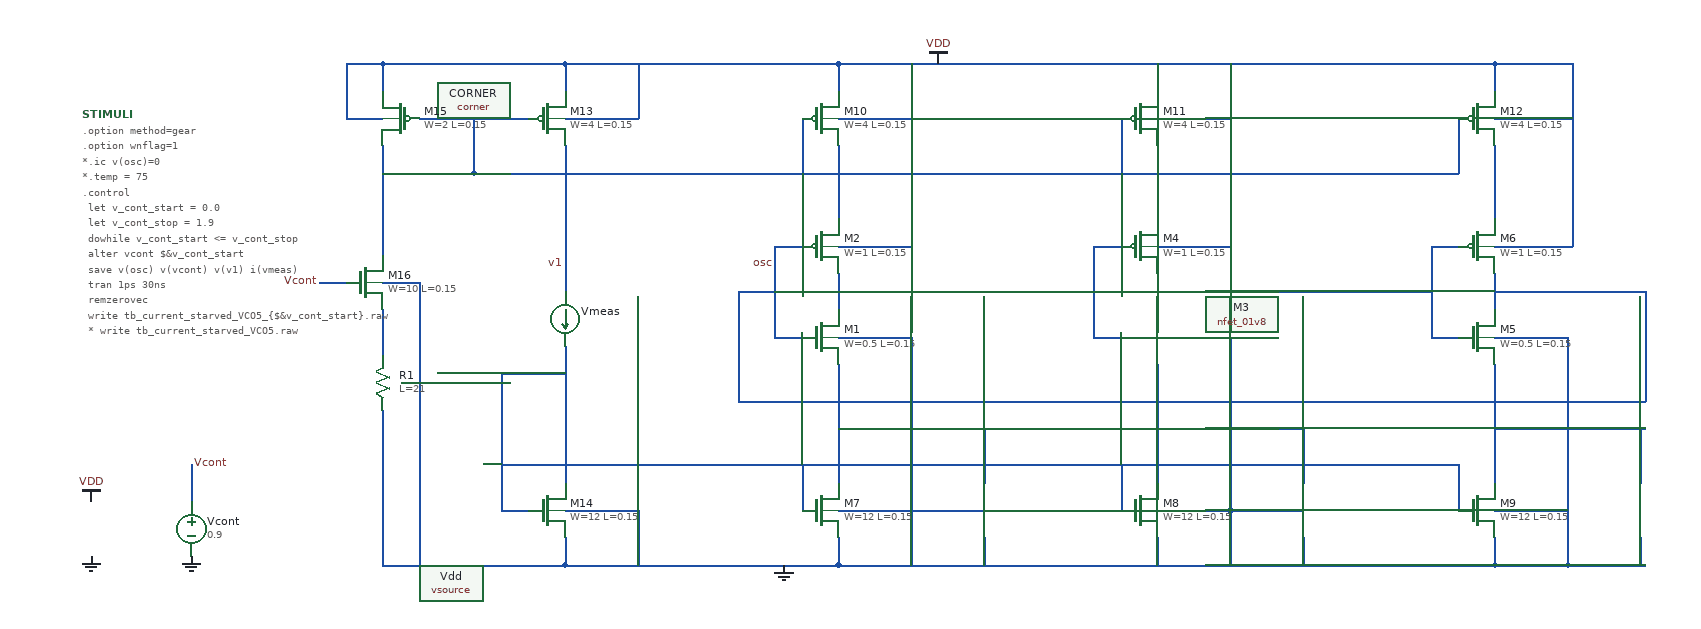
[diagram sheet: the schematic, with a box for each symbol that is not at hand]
v {xschem version=3.4.5 file_version=1.2
}
G {}
K {}
V {}
S {}
E {}
B 2 40 -1430 1140 -730 {flags=graph
y1=1.7
y2=1.8
ypos1=0
ypos2=2
divy=5
subdivy=1
unity=1
x1=0
x2=3e-08
divx=5
subdivx=1
xlabmag=1.0
ylabmag=1.0
node=osc
color=6
dataset=-1
unitx=1
logx=0
logy=0
}
N 880 -410 880 -370 {
lab=#net1}
N 810 -440 840 -440 {
lab=osc}
N 810 -440 810 -340 {
lab=osc}
N 810 -340 840 -340 {
lab=osc}
N 1230 -410 1230 -370 {
lab=#net2}
N 1160 -440 1190 -440 {
lab=#net1}
N 1160 -440 1160 -340 {
lab=#net1}
N 1160 -340 1190 -340 {
lab=#net1}
N 880 -390 1160 -390 {
lab=#net1}
N 1600 -410 1600 -370 {
lab=osc}
N 1530 -440 1560 -440 {
lab=#net2}
N 1530 -440 1530 -340 {
lab=#net2}
N 1530 -340 1560 -340 {
lab=#net2}
N 1230 -390 1530 -390 {
lab=#net2}
N 880 -120 880 -90 {
lab=GND}
N 880 -90 1600 -90 {
lab=GND}
N 1600 -120 1600 -90 {
lab=GND}
N 1230 -120 1230 -90 {
lab=GND}
N 1600 -390 1765 -390 {
lab=osc}
N 1765 -390 1765 -270 {
lab=osc}
N 770 -270 1765 -270 {
lab=osc}
N 770 -390 770 -270 {
lab=osc}
N 770 -390 810 -390 {
lab=osc}
N 880 -550 880 -470 {
lab=#net3}
N 880 -550 880 -470 {
lab=#net3}
N 1230 -550 1230 -470 {
lab=#net4}
N 1600 -550 1600 -470 {
lab=#net5}
N 880 -640 880 -610 {
lab=VDD}
N 880 -640 1600 -640 {
lab=VDD}
N 1600 -640 1600 -610 {
lab=VDD}
N 1230 -640 1230 -610 {
lab=VDD}
N 580 -640 580 -610 {
lab=VDD}
N 580 -640 880 -640 {
lab=VDD}
N 580 -120 580 -90 {
lab=GND}
N 580 -90 880 -90 {
lab=GND}
N 1600 -310 1600 -180 {
lab=#net6}
N 1230 -310 1230 -180 {
lab=#net7}
N 880 -310 880 -180 {
lab=#net8}
N 880 -440 960 -440 {
lab=VDD}
N 960 -640 960 -440 {
lab=VDD}
N 880 -340 960 -340 {
lab=GND}
N 960 -340 960 -90 {
lab=GND}
N 880 -150 960 -150 {
lab=GND}
N 1230 -340 1310 -340 {
lab=GND}
N 1310 -340 1310 -90 {
lab=GND}
N 1230 -150 1310 -150 {
lab=GND}
N 1600 -340 1680 -340 {
lab=GND}
N 1680 -340 1680 -90 {
lab=GND}
N 1600 -90 1680 -90 {
lab=GND}
N 880 -580 960 -580 {
lab=VDD}
N 1230 -580 1310 -580 {
lab=VDD}
N 1230 -440 1310 -440 {
lab=VDD}
N 1310 -640 1310 -440 {
lab=VDD}
N 1600 -580 1685 -580 {
lab=VDD}
N 1600 -640 1685 -640 {
lab=VDD}
N 1685 -640 1685 -440 {
lab=VDD}
N 1600 -440 1685 -440 {
lab=VDD}
N 1560 -580 1560 -520 {
lab=#net9}
N 1190 -580 1190 -520 {
lab=#net9}
N 510 -200 1560 -200 {
lab=#net10}
N 1560 -200 1560 -150 {
lab=#net10}
N 1190 -200 1190 -150 {
lab=#net10}
N 840 -200 840 -150 {
lab=#net10}
N 580 -580 660 -580 {
lab=VDD}
N 660 -640 660 -580 {
lab=VDD}
N 580 -640 660 -640 {
lab=VDD}
N 580 -150 660 -150 {
lab=GND}
N 660 -150 660 -90 {
lab=GND}
N 170 -200 170 -160 {
lab=Vcont}
N 580 -330 580 -180 {
lab=#net10}
N 580 -550 580 -390 {
lab=v1}
N 510 -300 580 -300 {
lab=#net10}
N 840 -580 840 -520 {
lab=#net9}
N 380 -640 380 -610 {
lab=VDD}
N 340 -580 380 -580 {
lab=VDD}
N 340 -640 340 -580 {
lab=VDD}
N 340 -640 380 -640 {
lab=VDD}
N 310 -400 340 -400 {
lab=Vcont}
N 380 -550 380 -430 {
lab=#net9}
N 420 -640 580 -640 {
lab=VDD}
N 380 -370 380 -320 {
lab=#net11}
N 380 -90 580 -90 {
lab=GND}
N 420 -190 420 -90 {
lab=GND}
N 420 -400 420 -190 {
lab=GND}
N 380 -400 420 -400 {
lab=GND}
N 380 -260 380 -90 {
lab=GND}
N 510 -150 540 -150 {
lab=#net10}
N 510 -300 510 -150 {
lab=#net10}
N 400 -290 420 -290 {
lab=GND}
N 480 -580 480 -520 {
lab=#net9}
N 960 -150 1040 -150 {
lab=GND}
N 880 -240 1040 -240 {
lab=#net8}
N 1310 -150 1390 -150 {
lab=GND}
N 1230 -240 1390 -240 {
lab=#net7}
N 1600 -240 1765 -240 {
lab=#net6}
N 1680 -90 1765 -90 {
lab=GND}
N 1040 -120 1040 -90 {
lab=GND}
N 1040 -240 1040 -180 {
lab=#net8}
N 1310 -150 1390 -150 {
lab=GND}
N 1390 -120 1390 -90 {
lab=GND}
N 1390 -240 1390 -180 {
lab=#net7}
N 1760 -120 1760 -90 {
lab=GND}
N 1760 -240 1760 -180 {
lab=#net6}
N 1600 -150 1680 -150 {
lab=GND}
N 380 -640 420 -640 {
lab=VDD}
N 420 -580 540 -580 {
lab=#net9}
N 480 -520 1560 -520 {
lab=#net9}
N 380 -520 480 -520 {
lab=#net9}
C {devices/vdd.sym} 990 -640 0 0 {name=l1 lab=VDD}
C {devices/gnd.sym} 820 -90 0 0 {name=l2 lab=GND}
C {sky130_fd_pr/nfet_01v8.sym} 860 -340 0 0 {name=M1
L=0.15
W=0.5
nf=1 
mult=1
ad="'int((nf+1)/2) * W/nf * 0.29'" 
pd="'2*int((nf+1)/2) * (W/nf + 0.29)'"
as="'int((nf+2)/2) * W/nf * 0.29'" 
ps="'2*int((nf+2)/2) * (W/nf + 0.29)'"
nrd="'0.29 / W'" nrs="'0.29 / W'"
sa=0 sb=0 sd=0
model=nfet_01v8
spiceprefix=X
}
C {sky130_fd_pr/pfet_01v8.sym} 860 -440 0 0 {name=M2
L=0.15
W=1
nf=2
mult=1
ad="'int((nf+1)/2) * W/nf * 0.29'" 
pd="'2*int((nf+1)/2) * (W/nf + 0.29)'"
as="'int((nf+2)/2) * W/nf * 0.29'" 
ps="'2*int((nf+2)/2) * (W/nf + 0.29)'"
nrd="'0.29 / W'" nrs="'0.29 / W'"
sa=0 sb=0 sd=0
model=pfet_01v8
spiceprefix=X
}
C {sky130_fd_pr/nfet_01v8.sym} 1200 -340 0 0 {name=M3
L=0.15
W=0.5
nf=1 
mult=1
ad="'int((nf+1)/2) * W/nf * 0.29'" 
pd="'2*int((nf+1)/2) * (W/nf + 0.29)'"
as="'int((nf+2)/2) * W/nf * 0.29'" 
ps="'2*int((nf+2)/2) * (W/nf + 0.29)'"
nrd="'0.29 / W'" nrs="'0.29 / W'"
sa=0 sb=0 sd=0
model=nfet_01v8
spiceprefix=X
}
C {sky130_fd_pr/pfet_01v8.sym} 1210 -440 0 0 {name=M4
L=0.15
W=1
nf=2
mult=1
ad="'int((nf+1)/2) * W/nf * 0.29'" 
pd="'2*int((nf+1)/2) * (W/nf + 0.29)'"
as="'int((nf+2)/2) * W/nf * 0.29'" 
ps="'2*int((nf+2)/2) * (W/nf + 0.29)'"
nrd="'0.29 / W'" nrs="'0.29 / W'"
sa=0 sb=0 sd=0
model=pfet_01v8
spiceprefix=X
}
C {sky130_fd_pr/nfet_01v8.sym} 1580 -340 0 0 {name=M5
L=0.15
W=0.5
nf=1 
mult=1
ad="'int((nf+1)/2) * W/nf * 0.29'" 
pd="'2*int((nf+1)/2) * (W/nf + 0.29)'"
as="'int((nf+2)/2) * W/nf * 0.29'" 
ps="'2*int((nf+2)/2) * (W/nf + 0.29)'"
nrd="'0.29 / W'" nrs="'0.29 / W'"
sa=0 sb=0 sd=0
model=nfet_01v8
spiceprefix=X
}
C {sky130_fd_pr/pfet_01v8.sym} 1580 -440 0 0 {name=M6
L=0.15
W=1
nf=2
mult=1
ad="'int((nf+1)/2) * W/nf * 0.29'" 
pd="'2*int((nf+1)/2) * (W/nf + 0.29)'"
as="'int((nf+2)/2) * W/nf * 0.29'" 
ps="'2*int((nf+2)/2) * (W/nf + 0.29)'"
nrd="'0.29 / W'" nrs="'0.29 / W'"
sa=0 sb=0 sd=0
model=pfet_01v8
spiceprefix=X
}
C {sky130_fd_pr/nfet_01v8.sym} 860 -150 0 0 {name=M7
L=0.15
W=12
nf=24 
mult=1
ad="'int((nf+1)/2) * W/nf * 0.29'" 
pd="'2*int((nf+1)/2) * (W/nf + 0.29)'"
as="'int((nf+2)/2) * W/nf * 0.29'" 
ps="'2*int((nf+2)/2) * (W/nf + 0.29)'"
nrd="'0.29 / W'" nrs="'0.29 / W'"
sa=0 sb=0 sd=0
model=nfet_01v8
spiceprefix=X
}
C {sky130_fd_pr/nfet_01v8.sym} 1210 -150 0 0 {name=M8
L=0.15
W=12
nf=24 
mult=1
ad="'int((nf+1)/2) * W/nf * 0.29'" 
pd="'2*int((nf+1)/2) * (W/nf + 0.29)'"
as="'int((nf+2)/2) * W/nf * 0.29'" 
ps="'2*int((nf+2)/2) * (W/nf + 0.29)'"
nrd="'0.29 / W'" nrs="'0.29 / W'"
sa=0 sb=0 sd=0
model=nfet_01v8
spiceprefix=X
}
C {sky130_fd_pr/nfet_01v8.sym} 1580 -150 0 0 {name=M9
L=0.15
W=12
nf=24 
mult=1
ad="'int((nf+1)/2) * W/nf * 0.29'" 
pd="'2*int((nf+1)/2) * (W/nf + 0.29)'"
as="'int((nf+2)/2) * W/nf * 0.29'" 
ps="'2*int((nf+2)/2) * (W/nf + 0.29)'"
nrd="'0.29 / W'" nrs="'0.29 / W'"
sa=0 sb=0 sd=0
model=nfet_01v8
spiceprefix=X
}
C {sky130_fd_pr/pfet_01v8.sym} 860 -580 0 0 {name=M10
L=0.15
W=4
nf=8
mult=1
ad="'int((nf+1)/2) * W/nf * 0.29'" 
pd="'2*int((nf+1)/2) * (W/nf + 0.29)'"
as="'int((nf+2)/2) * W/nf * 0.29'" 
ps="'2*int((nf+2)/2) * (W/nf + 0.29)'"
nrd="'0.29 / W'" nrs="'0.29 / W'"
sa=0 sb=0 sd=0
model=pfet_01v8
spiceprefix=X
}
C {sky130_fd_pr/pfet_01v8.sym} 1210 -580 0 0 {name=M11
L=0.15
W=4
nf=8
mult=1
ad="'int((nf+1)/2) * W/nf * 0.29'" 
pd="'2*int((nf+1)/2) * (W/nf + 0.29)'"
as="'int((nf+2)/2) * W/nf * 0.29'" 
ps="'2*int((nf+2)/2) * (W/nf + 0.29)'"
nrd="'0.29 / W'" nrs="'0.29 / W'"
sa=0 sb=0 sd=0
model=pfet_01v8
spiceprefix=X
}
C {sky130_fd_pr/pfet_01v8.sym} 1580 -580 0 0 {name=M12
L=0.15
W=4
nf=8
mult=1
ad="'int((nf+1)/2) * W/nf * 0.29'" 
pd="'2*int((nf+1)/2) * (W/nf + 0.29)'"
as="'int((nf+2)/2) * W/nf * 0.29'" 
ps="'2*int((nf+2)/2) * (W/nf + 0.29)'"
nrd="'0.29 / W'" nrs="'0.29 / W'"
sa=0 sb=0 sd=0
model=pfet_01v8
spiceprefix=X
}
C {devices/vsource.sym} 60 -130 0 0 {name=Vdd value=1.8 savecurrent=false
* "pwl()"}
C {devices/gnd.sym} 60 -100 0 0 {name=l3 lab=GND}
C {devices/vdd.sym} 60 -160 0 0 {name=l4 lab=VDD}
C {devices/vsource.sym} 170 -130 0 0 {name=Vcont value=0.9 savecurrent=false}
C {devices/gnd.sym} 170 -100 0 0 {name=l5 lab=GND}
C {sky130_fd_pr/pfet_01v8.sym} 560 -580 0 0 {name=M13
L=0.15
W=4
nf=8
mult=1
ad="'int((nf+1)/2) * W/nf * 0.29'" 
pd="'2*int((nf+1)/2) * (W/nf + 0.29)'"
as="'int((nf+2)/2) * W/nf * 0.29'" 
ps="'2*int((nf+2)/2) * (W/nf + 0.29)'"
nrd="'0.29 / W'" nrs="'0.29 / W'"
sa=0 sb=0 sd=0
model=pfet_01v8
spiceprefix=X
}
C {sky130_fd_pr/nfet_01v8.sym} 560 -150 0 0 {name=M14
L=0.15
W=12
nf=24 
mult=1
ad="'int((nf+1)/2) * W/nf * 0.29'" 
pd="'2*int((nf+1)/2) * (W/nf + 0.29)'"
as="'int((nf+2)/2) * W/nf * 0.29'" 
ps="'2*int((nf+2)/2) * (W/nf + 0.29)'"
nrd="'0.29 / W'" nrs="'0.29 / W'"
sa=0 sb=0 sd=0
model=nfet_01v8
spiceprefix=X
}
C {devices/lab_pin.sym} 170 -200 0 1 {name=p1 sig_type=std_logic lab=Vcont}
C {devices/lab_pin.sym} 310 -400 0 0 {name=p2 sig_type=std_logic lab=Vcont}
C {sky130_fd_pr/corner.sym} 50 -410 0 0 {name=CORNER only_toplevel=false corner=tt}
C {devices/code.sym} 50 -583.75 0 0 {name=STIMULI only_toplevel=false value="

.option method=gear
.option wnflag=1


*.ic v(osc)=0

*.temp = 75

.control
  let v_cont_start = 0.0
  let v_cont_stop = 1.9

  dowhile v_cont_start <= v_cont_stop
    alter vcont $&v_cont_start
    save v(osc) v(vcont) v(v1) i(vmeas)
    tran 1ps 30ns
    remzerovec
    write tb_current_starved_VCO5_\{$&v_cont_start\}.raw
    * write tb_current_starved_VCO5.raw
    let filename = v_cont_start * 100
    wrdata /foss/designs/my_design/projects/pll/vco/xschem_ngspice/tb_current_starved_VCO5_\{$&filename\}.txt v(osc)
    set appendwrite

    reset
    let v_cont_start = v_cont_start + 0.1
  end
.endc




"}
C {devices/lab_pin.sym} 810 -420 0 0 {name=p3 sig_type=std_logic lab=osc}
C {devices/lab_pin.sym} 580 -420 0 0 {name=p4 sig_type=std_logic lab=v1}
C {devices/ammeter.sym} 580 -360 0 0 {name=Vmeas savecurrent=true spice_ignore=0}
C {sky130_fd_pr/pfet_01v8.sym} 400 -580 0 1 {name=M15
L=0.15
W=2
nf=4
mult=1
ad="'int((nf+1)/2) * W/nf * 0.29'" 
pd="'2*int((nf+1)/2) * (W/nf + 0.29)'"
as="'int((nf+2)/2) * W/nf * 0.29'" 
ps="'2*int((nf+2)/2) * (W/nf + 0.29)'"
nrd="'0.29 / W'" nrs="'0.29 / W'"
sa=0 sb=0 sd=0
model=pfet_01v8
spiceprefix=X
}
C {sky130_fd_pr/nfet_01v8.sym} 360 -400 0 0 {name=M16
L=0.15
W=10
nf=10 
mult=12
ad="'int((nf+1)/2) * W/nf * 0.29'" 
pd="'2*int((nf+1)/2) * (W/nf + 0.29)'"
as="'int((nf+2)/2) * W/nf * 0.29'" 
ps="'2*int((nf+2)/2) * (W/nf + 0.29)'"
nrd="'0.29 / W'" nrs="'0.29 / W'"
sa=0 sb=0 sd=0
model=nfet_01v8
spiceprefix=X
}
C {sky130_fd_pr/res_xhigh_po_0p35.sym} 380 -290 0 1 {name=R1
L=21
model=res_xhigh_po_0p35
spiceprefix=X
mult=1}
